VERSION 5.8 ;
DIVIDERCHAR "/" ;
BUSBITCHARS "[]" ;

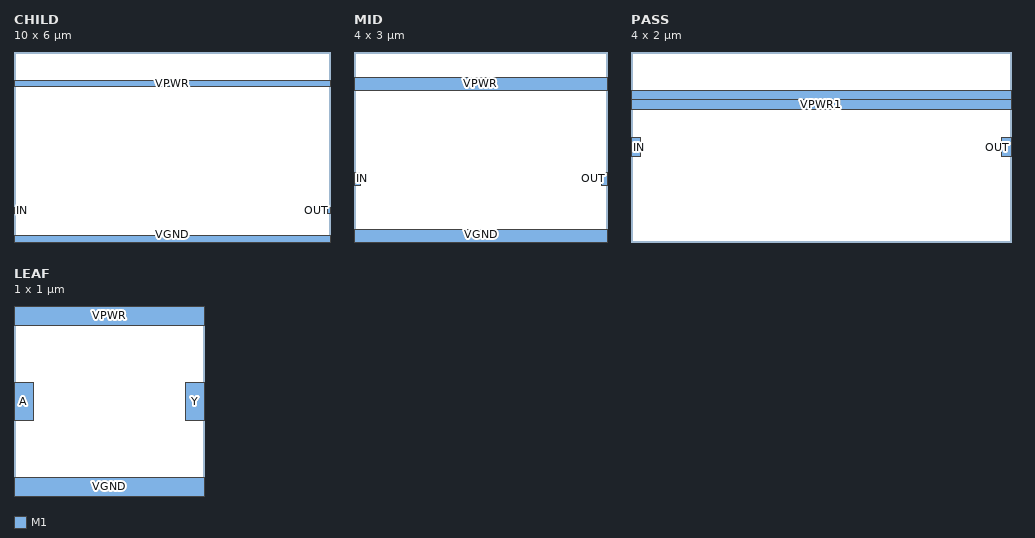
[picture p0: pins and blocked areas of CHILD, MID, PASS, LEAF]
MACRO CHILD
  CLASS BLOCK ;
  ORIGIN 0.000 0.000 ;
  SIZE 10.000 BY 6.000 ;
  SYMMETRY X Y R90 ;
  PIN IN
    DIRECTION INPUT ;
    USE SIGNAL ;
    PORT
      LAYER M1 ;
        RECT 0.000 0.900 0.100 1.100 ;
    END
  END IN
  PIN OUT
    DIRECTION OUTPUT ;
    USE SIGNAL ;
    PORT
      LAYER M1 ;
        RECT 9.900 0.900 10.000 1.100 ;
    END
  END OUT
  PIN VPWR
    DIRECTION INOUT ;
    USE POWER ;
    PORT
      LAYER M1 ;
        RECT 0.000 4.900 10.000 5.100 ;
    END
  END VPWR
  PIN VGND
    DIRECTION INOUT ;
    USE GROUND ;
    PORT
      LAYER M1 ;
        RECT 0.000 0.000 10.000 0.200 ;
    END
  END VGND
END CHILD

MACRO MID
  CLASS BLOCK ;
  ORIGIN 0.000 0.000 ;
  SIZE 4.000 BY 3.000 ;
  SYMMETRY X Y R90 ;
  PIN IN
    DIRECTION INPUT ;
    USE SIGNAL ;
    PORT
      LAYER M1 ;
        RECT 0.000 0.900 0.100 1.100 ;
    END
  END IN
  PIN OUT
    DIRECTION OUTPUT ;
    USE SIGNAL ;
    PORT
      LAYER M1 ;
        RECT 3.900 0.900 4.000 1.100 ;
    END
  END OUT
  PIN VPWR
    DIRECTION INOUT ;
    USE POWER ;
    PORT
      LAYER M1 ;
        RECT 0.000 2.400 4.000 2.600 ;
    END
  END VPWR
  PIN VGND
    DIRECTION INOUT ;
    USE GROUND ;
    PORT
      LAYER M1 ;
        RECT 0.000 0.000 4.000 0.200 ;
    END
  END VGND
END MID

MACRO ALT
  CLASS BLOCK ;
  ORIGIN 0.000 0.000 ;
  SIZE 4.000 BY 3.000 ;
  SYMMETRY X Y R90 ;
END ALT

MACRO PASS
  CLASS BLOCK ;
  ORIGIN 0.000 0.000 ;
  SIZE 4.000 BY 2.000 ;
  SYMMETRY X Y R90 ;
  PIN IN
    DIRECTION INPUT ;
    USE SIGNAL ;
    PORT
      LAYER M1 ;
        RECT 0.000 0.900 0.100 1.100 ;
    END
  END IN
  PIN OUT
    DIRECTION OUTPUT ;
    USE SIGNAL ;
    PORT
      LAYER M1 ;
        RECT 3.900 0.900 4.000 1.100 ;
    END
  END OUT
  PIN VPWR1
    DIRECTION INOUT ;
    USE POWER ;
    PORT
      LAYER M1 ;
        RECT 0.000 1.400 4.000 1.500 ;
    END
  END VPWR1
  PIN VPWR2
    DIRECTION INOUT ;
    USE POWER ;
    PORT
      LAYER M1 ;
        RECT 0.000 1.500 4.000 1.600 ;
    END
  END VPWR2
END PASS

MACRO LEAF
  CLASS CORE ;
  ORIGIN 0.000 0.000 ;
  SIZE 1.000 BY 1.000 ;
  SYMMETRY X Y R90 ;
  PIN A
    DIRECTION INPUT ;
    USE SIGNAL ;
    PORT
      LAYER M1 ;
        RECT 0.000 0.400 0.100 0.600 ;
    END
  END A
  PIN Y
    DIRECTION OUTPUT ;
    USE SIGNAL ;
    PORT
      LAYER M1 ;
        RECT 0.900 0.400 1.000 0.600 ;
    END
  END Y
  PIN VPWR
    DIRECTION INOUT ;
    USE POWER ;
    PORT
      LAYER M1 ;
        RECT 0.000 0.900 1.000 1.000 ;
    END
  END VPWR
  PIN VGND
    DIRECTION INOUT ;
    USE GROUND ;
    PORT
      LAYER M1 ;
        RECT 0.000 0.000 1.000 0.100 ;
    END
  END VGND
END LEAF

END LIBRARY
